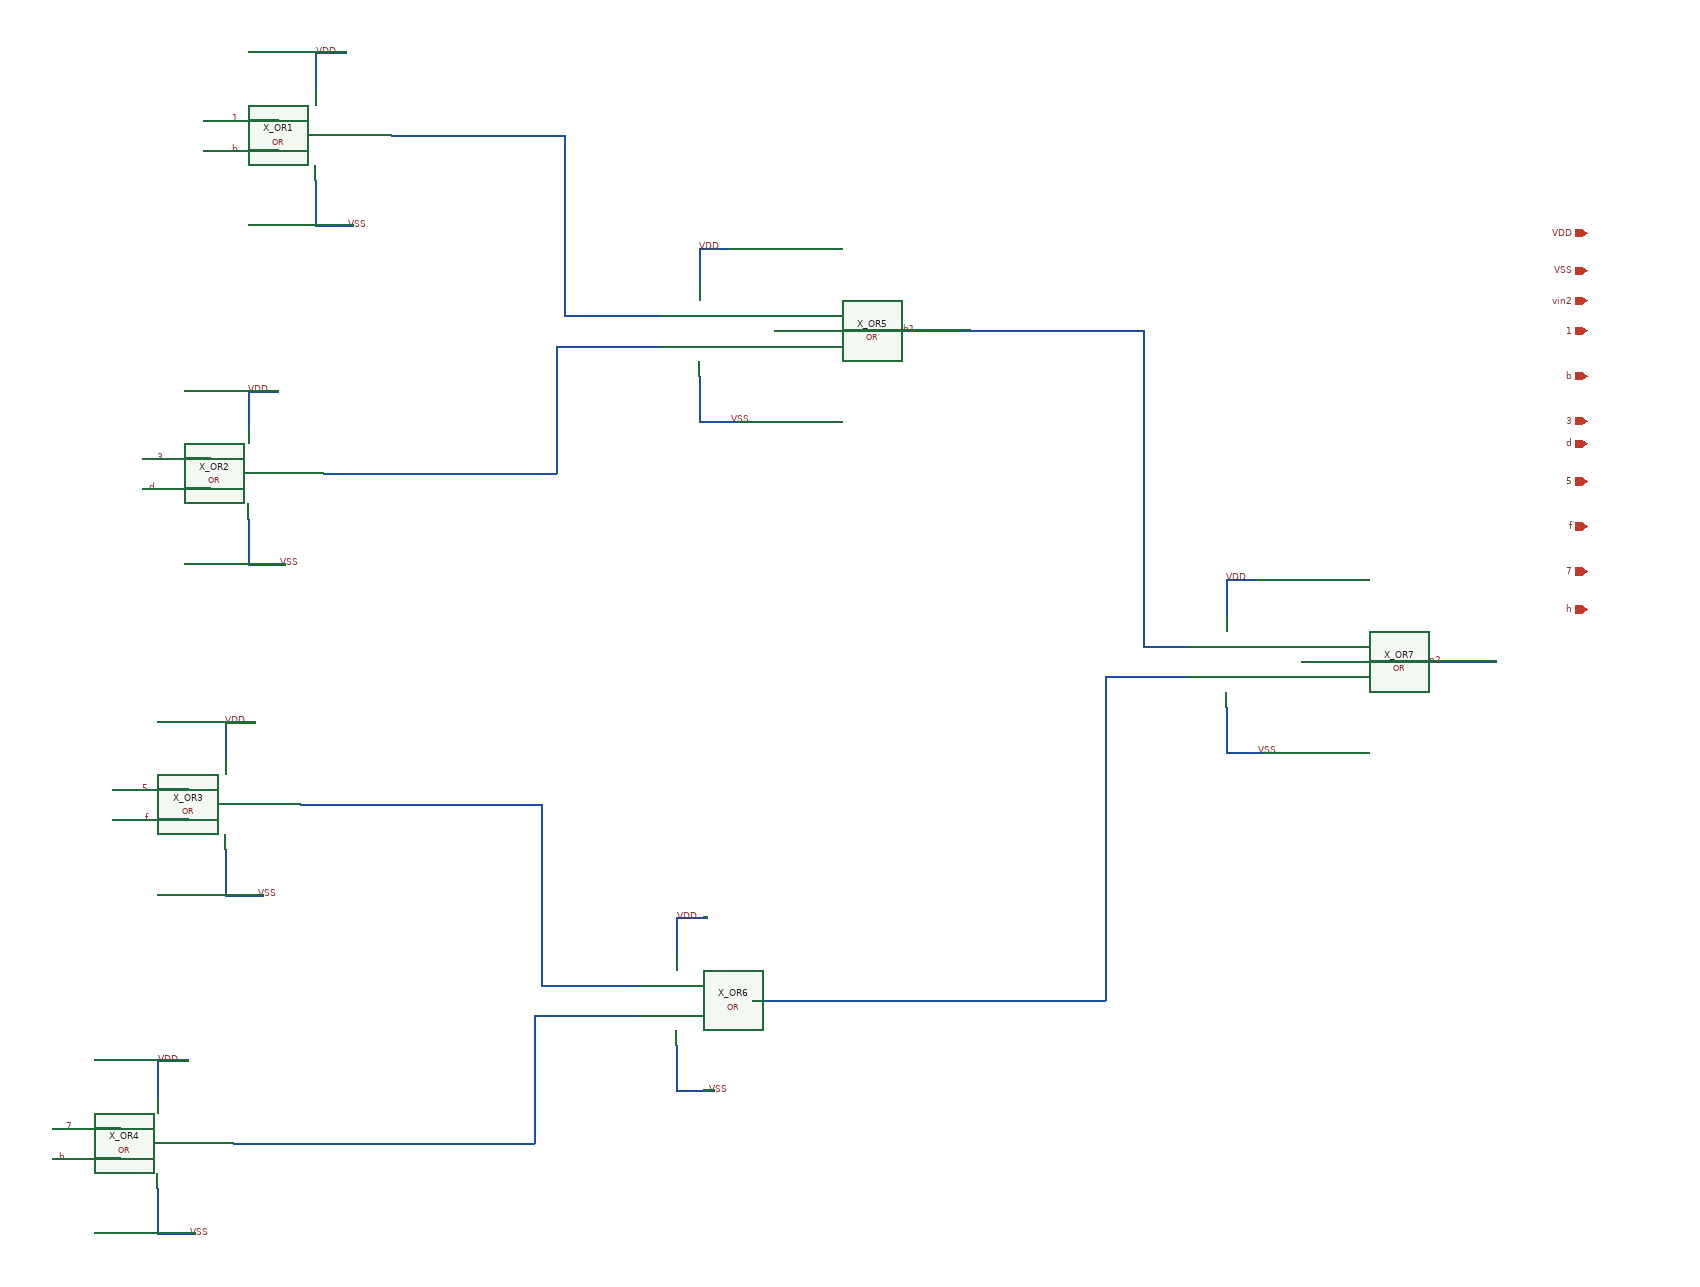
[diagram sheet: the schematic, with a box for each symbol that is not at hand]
v {xschem version=3.0.0 file_version=1.2 }
G {}
K {}
V {}
S {}
E {}
N -1590 -1820 -1500 -1820 {
lab=#net1}
N -1590 -1370 -1500 -1370 {
lab=#net2}
N -1400 -1580 -1270 -1580 {
lab=#net1}
N -1400 -1820 -1400 -1580 {
lab=#net1}
N -1500 -1820 -1400 -1820 {
lab=#net1}
N -1410 -1540 -1270 -1540 {
lab=#net2}
N -1410 -1540 -1410 -1370 {
lab=#net2}
N -1500 -1370 -1410 -1370 {
lab=#net2}
N -990 -1560 -860 -1560 {
lab=ph1}
N -1880 -1840 -1780 -1840 {
lab=1}
N -1880 -1800 -1780 -1800 {
lab=b}
N -1960 -1390 -1870 -1390 {
lab=3}
N -1960 -1350 -1870 -1350 {
lab=d}
N -1620 -930 -1530 -930 {
lab=#net3}
N -1620 -480 -1530 -480 {
lab=#net4}
N -1430 -690 -1300 -690 {
lab=#net3}
N -1430 -930 -1430 -690 {
lab=#net3}
N -1530 -930 -1430 -930 {
lab=#net3}
N -1440 -650 -1300 -650 {
lab=#net4}
N -1440 -650 -1440 -480 {
lab=#net4}
N -1530 -480 -1440 -480 {
lab=#net4}
N -930 -670 -800 -670 {
lab=#net5}
N -2000 -950 -1900 -950 {
lab=5}
N -2000 -910 -1900 -910 {
lab=f}
N -2080 -500 -1990 -500 {
lab=7}
N -2080 -460 -1990 -460 {
lab=h}
N -290 -1120 -160 -1120 {
lab=vin2}
N -870 -1560 -630 -1560 {
lab=ph1}
N -630 -1560 -630 -1140 {
lab=ph1}
N -630 -1140 -570 -1140 {
lab=ph1}
N -800 -670 -680 -670 {
lab=#net5}
N -680 -1090 -680 -670 {
lab=#net5}
N -1630 -1820 -1590 -1820 {
lab=#net1}
N -1730 -1930 -1730 -1880 {
lab=VDD}
N -1730 -1930 -1690 -1930 {
lab=VDD}
N -1730 -1760 -1730 -1700 {
lab=VSS}
N -1730 -1700 -1680 -1700 {
lab=VSS}
N -1680 -1370 -1590 -1370 {
lab=#net2}
N -1720 -1370 -1680 -1370 {
lab=#net2}
N -1820 -1480 -1820 -1430 {
lab=VDD}
N -1820 -1480 -1780 -1480 {
lab=VDD}
N -1820 -1310 -1820 -1250 {
lab=VSS}
N -1820 -1250 -1770 -1250 {
lab=VSS}
N -1710 -930 -1620 -930 {
lab=#net3}
N -1750 -930 -1710 -930 {
lab=#net3}
N -1850 -1040 -1850 -990 {
lab=VDD}
N -1850 -1040 -1810 -1040 {
lab=VDD}
N -1850 -870 -1850 -810 {
lab=VSS}
N -1850 -810 -1800 -810 {
lab=VSS}
N -1710 -480 -1620 -480 {
lab=#net4}
N -1800 -480 -1710 -480 {
lab=#net4}
N -1840 -480 -1800 -480 {
lab=#net4}
N -1940 -590 -1940 -540 {
lab=VDD}
N -1940 -590 -1900 -590 {
lab=VDD}
N -1940 -420 -1940 -360 {
lab=VSS}
N -1940 -360 -1890 -360 {
lab=VSS}
N -1080 -1560 -990 -1560 {
lab=ph1}
N -1120 -1560 -1080 -1560 {
lab=ph1}
N -1220 -1670 -1220 -1620 {
lab=VDD}
N -1220 -1670 -1180 -1670 {
lab=VDD}
N -1220 -1500 -1220 -1440 {
lab=VSS}
N -1220 -1440 -1170 -1440 {
lab=VSS}
N -1020 -670 -930 -670 {
lab=#net5}
N -1110 -670 -1020 -670 {
lab=#net5}
N -1150 -670 -1110 -670 {
lab=#net5}
N -1250 -780 -1250 -730 {
lab=VDD}
N -1250 -780 -1210 -780 {
lab=VDD}
N -1250 -610 -1250 -550 {
lab=VSS}
N -1250 -550 -1200 -550 {
lab=VSS}
N -380 -1120 -290 -1120 {
lab=vin2}
N -420 -1120 -380 -1120 {
lab=vin2}
N -520 -1230 -520 -1180 {
lab=VDD}
N -520 -1230 -480 -1230 {
lab=VDD}
N -520 -1060 -520 -1000 {
lab=VSS}
N -520 -1000 -470 -1000 {
lab=VSS}
N -680 -1100 -570 -1100 {
lab=#net5}
N -680 -1100 -680 -1090 {
lab=#net5}
C {devices/lab_wire.sym} -1830 -1840 0 0 {name=l178 sig_type=std_logic lab=1}
C {devices/lab_wire.sym} -1830 -1800 0 0 {name=l179 sig_type=std_logic lab=b}
C {devices/lab_wire.sym} -1930 -1390 0 0 {name=l180 sig_type=std_logic lab=3}
C {devices/lab_wire.sym} -1940 -1350 0 0 {name=l181 sig_type=std_logic lab=d}
C {devices/lab_wire.sym} -930 -1560 0 0 {name=l182 sig_type=std_logic lab=ph1}
C {devices/lab_wire.sym} -1950 -950 0 0 {name=l195 sig_type=std_logic lab=5}
C {devices/lab_wire.sym} -1950 -910 0 0 {name=l196 sig_type=std_logic lab=f}
C {devices/lab_wire.sym} -2050 -500 0 0 {name=l197 sig_type=std_logic lab=7}
C {devices/lab_wire.sym} -2060 -460 0 0 {name=l198 sig_type=std_logic lab=h}
C {devices/lab_wire.sym} -230 -1120 0 0 {name=l216 sig_type=std_logic lab=vin2}
C {devices/lab_wire.sym} -1700 -1930 0 0 {name=l4 sig_type=std_logic lab=VDD}
C {devices/lab_wire.sym} -1690 -1700 0 1 {name=l14 sig_type=std_logic lab=VSS}
C {DC_DC_Converter/Delay_block_revised/OR_GATE/OR.sym} -1800 -1750 0 0 {name=X_OR1}
C {devices/lab_wire.sym} -1790 -1480 0 0 {name=l24 sig_type=std_logic lab=VDD}
C {devices/lab_wire.sym} -1780 -1250 0 1 {name=l34 sig_type=std_logic lab=VSS}
C {DC_DC_Converter/Delay_block_revised/OR_GATE/OR.sym} -1890 -1300 0 0 {name=X_OR2}
C {devices/lab_wire.sym} -1820 -1040 0 0 {name=l41 sig_type=std_logic lab=VDD}
C {devices/lab_wire.sym} -1810 -810 0 1 {name=l44 sig_type=std_logic lab=VSS}
C {DC_DC_Converter/Delay_block_revised/OR_GATE/OR.sym} -1920 -860 0 0 {name=X_OR3}
C {devices/lab_wire.sym} -1910 -590 0 0 {name=l46 sig_type=std_logic lab=VDD}
C {devices/lab_wire.sym} -1900 -360 0 1 {name=l80 sig_type=std_logic lab=VSS}
C {DC_DC_Converter/Delay_block_revised/OR_GATE/OR.sym} -2010 -410 0 0 {name=X_OR4}
C {devices/lab_wire.sym} -1190 -1670 0 0 {name=l81 sig_type=std_logic lab=VDD}
C {devices/lab_wire.sym} -1180 -1440 0 1 {name=l82 sig_type=std_logic lab=VSS}
C {DC_DC_Converter/Delay_block_revised/OR_GATE/OR.sym} -1290 -1490 0 0 {name=X_OR5}
C {devices/lab_wire.sym} -1220 -780 0 0 {name=l85 sig_type=std_logic lab=VDD}
C {devices/lab_wire.sym} -1210 -550 0 1 {name=l92 sig_type=std_logic lab=VSS}
C {DC_DC_Converter/Delay_block_revised/OR_GATE/OR.sym} -1320 -600 0 0 {name=X_OR6}
C {devices/lab_wire.sym} -490 -1230 0 0 {name=l83 sig_type=std_logic lab=VDD}
C {devices/lab_wire.sym} -480 -1000 0 1 {name=l84 sig_type=std_logic lab=VSS}
C {DC_DC_Converter/Delay_block_revised/OR_GATE/OR.sym} -590 -1050 0 0 {name=X_OR7}
C {devices/iopin.sym} -40 -1690 0 0 {name=p1 lab=VDD}
C {devices/iopin.sym} -40 -1640 0 0 {name=p2 lab=VSS}
C {devices/iopin.sym} -40 -1600 0 0 {name=p3 lab=vin2}
C {devices/iopin.sym} -40 -1560 0 0 {name=p4 lab=1}
C {devices/iopin.sym} -40 -1500 0 0 {name=p5 lab=b}
C {devices/iopin.sym} -40 -1440 0 0 {name=p6 lab=3}
C {devices/iopin.sym} -40 -1410 0 0 {name=p7 lab=d}
C {devices/iopin.sym} -40 -1360 0 0 {name=p8 lab=5}
C {devices/iopin.sym} -40 -1300 0 0 {name=p9 lab=f}
C {devices/iopin.sym} -40 -1240 0 0 {name=p10 lab=7}
C {devices/iopin.sym} -40 -1190 0 0 {name=p11 lab=h}
